VERSION 5.7 ;
  NOWIREEXTENSIONATPIN ON ;
  DIVIDERCHAR "/" ;
  BUSBITCHARS "[]" ;
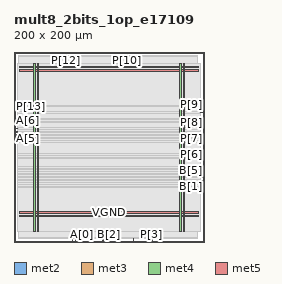
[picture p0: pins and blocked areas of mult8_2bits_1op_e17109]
MACRO mult8_2bits_1op_e17109
  CLASS BLOCK ;
  FOREIGN mult8_2bits_1op_e17109 ;
  ORIGIN 0.000 0.000 ;
  SIZE 200.000 BY 200.000 ;
  PIN A[0]
    DIRECTION INPUT ;
    USE SIGNAL ;
    ANTENNAGATEAREA 0.247500 ;
    PORT
      LAYER met2 ;
        RECT 70.930 0.000 71.210 4.000 ;
    END
  END A[0]
  PIN A[1]
    DIRECTION INPUT ;
    USE SIGNAL ;
    ANTENNAGATEAREA 0.159000 ;
    PORT
      LAYER met2 ;
        RECT 67.710 0.000 67.990 4.000 ;
    END
  END A[1]
  PIN A[2]
    DIRECTION INPUT ;
    USE SIGNAL ;
    ANTENNAGATEAREA 0.196500 ;
    PORT
      LAYER met2 ;
        RECT 61.270 0.000 61.550 4.000 ;
    END
  END A[2]
  PIN A[3]
    DIRECTION INPUT ;
    USE SIGNAL ;
    ANTENNAGATEAREA 0.159000 ;
    PORT
      LAYER met2 ;
        RECT 64.490 0.000 64.770 4.000 ;
    END
  END A[3]
  PIN A[4]
    DIRECTION INPUT ;
    USE SIGNAL ;
    ANTENNAGATEAREA 0.196500 ;
    PORT
      LAYER met3 ;
        RECT 196.000 71.440 200.000 72.040 ;
    END
  END A[4]
  PIN A[5]
    DIRECTION INPUT ;
    USE SIGNAL ;
    ANTENNAGATEAREA 0.213000 ;
    PORT
      LAYER met3 ;
        RECT 0.000 108.840 4.000 109.440 ;
    END
  END A[5]
  PIN A[6]
    DIRECTION INPUT ;
    USE SIGNAL ;
    ANTENNAGATEAREA 0.196500 ;
    PORT
      LAYER met3 ;
        RECT 0.000 119.040 4.000 119.640 ;
    END
  END A[6]
  PIN A[7]
    DIRECTION INPUT ;
    USE SIGNAL ;
    ANTENNAGATEAREA 0.159000 ;
    PORT
      LAYER met3 ;
        RECT 0.000 115.640 4.000 116.240 ;
    END
  END A[7]
  PIN B[0]
    DIRECTION INPUT ;
    USE SIGNAL ;
    ANTENNAGATEAREA 0.159000 ;
    PORT
      LAYER met3 ;
        RECT 196.000 78.240 200.000 78.840 ;
    END
  END B[0]
  PIN B[1]
    DIRECTION INPUT ;
    USE SIGNAL ;
    ANTENNAGATEAREA 0.495000 ;
    PORT
      LAYER met3 ;
        RECT 196.000 57.840 200.000 58.440 ;
    END
  END B[1]
  PIN B[2]
    DIRECTION INPUT ;
    USE SIGNAL ;
    ANTENNAGATEAREA 0.213000 ;
    PORT
      LAYER met2 ;
        RECT 99.910 0.000 100.190 4.000 ;
    END
  END B[2]
  PIN B[3]
    DIRECTION INPUT ;
    USE SIGNAL ;
    ANTENNAGATEAREA 0.196500 ;
    PORT
      LAYER met2 ;
        RECT 96.690 0.000 96.970 4.000 ;
    END
  END B[3]
  PIN B[4]
    DIRECTION INPUT ;
    USE SIGNAL ;
    ANTENNAGATEAREA 0.213000 ;
    PORT
      LAYER met3 ;
        RECT 196.000 61.240 200.000 61.840 ;
    END
  END B[4]
  PIN B[5]
    DIRECTION INPUT ;
    USE SIGNAL ;
    ANTENNAGATEAREA 0.495000 ;
    PORT
      LAYER met3 ;
        RECT 196.000 74.840 200.000 75.440 ;
    END
  END B[5]
  PIN B[6]
    DIRECTION INPUT ;
    USE SIGNAL ;
    ANTENNAGATEAREA 0.213000 ;
    PORT
      LAYER met3 ;
        RECT 0.000 105.440 4.000 106.040 ;
    END
  END B[6]
  PIN B[7]
    DIRECTION INPUT ;
    USE SIGNAL ;
    ANTENNAGATEAREA 0.196500 ;
    PORT
      LAYER met3 ;
        RECT 0.000 112.240 4.000 112.840 ;
    END
  END B[7]
  PIN P[0]
    DIRECTION OUTPUT ;
    USE SIGNAL ;
    ANTENNADIFFAREA 0.445500 ;
    PORT
      LAYER met3 ;
        RECT 196.000 88.440 200.000 89.040 ;
    END
  END P[0]
  PIN P[10]
    DIRECTION OUTPUT ;
    USE SIGNAL ;
    ANTENNADIFFAREA 1.336500 ;
    PORT
      LAYER met2 ;
        RECT 119.230 196.000 119.510 200.000 ;
    END
  END P[10]
  PIN P[11]
    DIRECTION OUTPUT ;
    USE SIGNAL ;
    ANTENNADIFFAREA 1.336500 ;
    PORT
      LAYER met2 ;
        RECT 106.350 196.000 106.630 200.000 ;
    END
  END P[11]
  PIN P[12]
    DIRECTION OUTPUT ;
    USE SIGNAL ;
    ANTENNADIFFAREA 1.336500 ;
    PORT
      LAYER met2 ;
        RECT 54.830 196.000 55.110 200.000 ;
    END
  END P[12]
  PIN P[13]
    DIRECTION OUTPUT ;
    USE SIGNAL ;
    ANTENNADIFFAREA 1.336500 ;
    PORT
      LAYER met3 ;
        RECT 0.000 142.840 4.000 143.440 ;
    END
  END P[13]
  PIN P[14]
    DIRECTION OUTPUT ;
    USE SIGNAL ;
    ANTENNADIFFAREA 1.336500 ;
    PORT
      LAYER met3 ;
        RECT 0.000 129.240 4.000 129.840 ;
    END
  END P[14]
  PIN P[15]
    DIRECTION OUTPUT ;
    USE SIGNAL ;
    ANTENNADIFFAREA 1.336500 ;
    PORT
      LAYER met3 ;
        RECT 0.000 125.840 4.000 126.440 ;
    END
  END P[15]
  PIN P[1]
    DIRECTION OUTPUT ;
    USE SIGNAL ;
    ANTENNADIFFAREA 0.445500 ;
    PORT
      LAYER met2 ;
        RECT 93.470 0.000 93.750 4.000 ;
    END
  END P[1]
  PIN P[2]
    DIRECTION OUTPUT ;
    USE SIGNAL ;
    ANTENNADIFFAREA 0.445500 ;
    PORT
      LAYER met2 ;
        RECT 125.670 0.000 125.950 4.000 ;
    END
  END P[2]
  PIN P[3]
    DIRECTION OUTPUT ;
    USE SIGNAL ;
    ANTENNADIFFAREA 0.445500 ;
    PORT
      LAYER met2 ;
        RECT 144.990 0.000 145.270 4.000 ;
    END
  END P[3]
  PIN P[4]
    DIRECTION OUTPUT ;
    USE SIGNAL ;
    ANTENNADIFFAREA 0.445500 ;
    PORT
      LAYER met3 ;
        RECT 196.000 64.640 200.000 65.240 ;
    END
  END P[4]
  PIN P[5]
    DIRECTION OUTPUT ;
    USE SIGNAL ;
    ANTENNADIFFAREA 0.445500 ;
    PORT
      LAYER met3 ;
        RECT 196.000 68.040 200.000 68.640 ;
    END
  END P[5]
  PIN P[6]
    DIRECTION OUTPUT ;
    USE SIGNAL ;
    ANTENNADIFFAREA 1.782000 ;
    PORT
      LAYER met3 ;
        RECT 196.000 91.840 200.000 92.440 ;
    END
  END P[6]
  PIN P[7]
    DIRECTION OUTPUT ;
    USE SIGNAL ;
    ANTENNADIFFAREA 1.782000 ;
    PORT
      LAYER met3 ;
        RECT 196.000 108.840 200.000 109.440 ;
    END
  END P[7]
  PIN P[8]
    DIRECTION OUTPUT ;
    USE SIGNAL ;
    ANTENNADIFFAREA 1.336500 ;
    PORT
      LAYER met3 ;
        RECT 196.000 125.840 200.000 126.440 ;
    END
  END P[8]
  PIN P[9]
    DIRECTION OUTPUT ;
    USE SIGNAL ;
    ANTENNADIFFAREA 1.336500 ;
    PORT
      LAYER met3 ;
        RECT 196.000 136.040 200.000 136.640 ;
    END
  END P[9]
  PIN VGND
    DIRECTION INOUT ;
    USE GROUND ;
    PORT
      LAYER met4 ;
        RECT 24.340 10.640 25.940 187.920 ;
    END
    PORT
      LAYER met4 ;
        RECT 177.940 10.640 179.540 187.920 ;
    END
    PORT
      LAYER met5 ;
        RECT 5.280 30.030 194.360 31.630 ;
    END
    PORT
      LAYER met5 ;
        RECT 5.280 183.210 194.360 184.810 ;
    END
  END VGND
  PIN VPWR
    DIRECTION INOUT ;
    USE POWER ;
    PORT
      LAYER met4 ;
        RECT 21.040 10.640 22.640 187.920 ;
    END
    PORT
      LAYER met4 ;
        RECT 174.640 10.640 176.240 187.920 ;
    END
    PORT
      LAYER met5 ;
        RECT 5.280 26.730 194.360 28.330 ;
    END
    PORT
      LAYER met5 ;
        RECT 5.280 179.910 194.360 181.510 ;
    END
  END VPWR
  OBS
      LAYER nwell ;
        RECT 5.330 10.795 194.310 187.870 ;
      LAYER li1 ;
        RECT 5.520 10.795 194.120 187.765 ;
      LAYER met1 ;
        RECT 4.210 10.640 194.120 187.920 ;
      LAYER met2 ;
        RECT 4.230 195.720 54.550 196.000 ;
        RECT 55.390 195.720 106.070 196.000 ;
        RECT 106.910 195.720 118.950 196.000 ;
        RECT 119.790 195.720 192.650 196.000 ;
        RECT 4.230 4.280 192.650 195.720 ;
        RECT 4.230 4.000 60.990 4.280 ;
        RECT 61.830 4.000 64.210 4.280 ;
        RECT 65.050 4.000 67.430 4.280 ;
        RECT 68.270 4.000 70.650 4.280 ;
        RECT 71.490 4.000 93.190 4.280 ;
        RECT 94.030 4.000 96.410 4.280 ;
        RECT 97.250 4.000 99.630 4.280 ;
        RECT 100.470 4.000 125.390 4.280 ;
        RECT 126.230 4.000 144.710 4.280 ;
        RECT 145.550 4.000 192.650 4.280 ;
      LAYER met3 ;
        RECT 3.990 143.840 196.000 187.845 ;
        RECT 4.400 142.440 196.000 143.840 ;
        RECT 3.990 137.040 196.000 142.440 ;
        RECT 3.990 135.640 195.600 137.040 ;
        RECT 3.990 130.240 196.000 135.640 ;
        RECT 4.400 128.840 196.000 130.240 ;
        RECT 3.990 126.840 196.000 128.840 ;
        RECT 4.400 125.440 195.600 126.840 ;
        RECT 3.990 120.040 196.000 125.440 ;
        RECT 4.400 118.640 196.000 120.040 ;
        RECT 3.990 116.640 196.000 118.640 ;
        RECT 4.400 115.240 196.000 116.640 ;
        RECT 3.990 113.240 196.000 115.240 ;
        RECT 4.400 111.840 196.000 113.240 ;
        RECT 3.990 109.840 196.000 111.840 ;
        RECT 4.400 108.440 195.600 109.840 ;
        RECT 3.990 106.440 196.000 108.440 ;
        RECT 4.400 105.040 196.000 106.440 ;
        RECT 3.990 92.840 196.000 105.040 ;
        RECT 3.990 91.440 195.600 92.840 ;
        RECT 3.990 89.440 196.000 91.440 ;
        RECT 3.990 88.040 195.600 89.440 ;
        RECT 3.990 79.240 196.000 88.040 ;
        RECT 3.990 77.840 195.600 79.240 ;
        RECT 3.990 75.840 196.000 77.840 ;
        RECT 3.990 74.440 195.600 75.840 ;
        RECT 3.990 72.440 196.000 74.440 ;
        RECT 3.990 71.040 195.600 72.440 ;
        RECT 3.990 69.040 196.000 71.040 ;
        RECT 3.990 67.640 195.600 69.040 ;
        RECT 3.990 65.640 196.000 67.640 ;
        RECT 3.990 64.240 195.600 65.640 ;
        RECT 3.990 62.240 196.000 64.240 ;
        RECT 3.990 60.840 195.600 62.240 ;
        RECT 3.990 58.840 196.000 60.840 ;
        RECT 3.990 57.440 195.600 58.840 ;
        RECT 3.990 10.715 196.000 57.440 ;
  END
END mult8_2bits_1op_e17109
END LIBRARY

